# Generated by FakeRAM 2.0
VERSION 5.7 ;
BUSBITCHARS "[]" ;
PROPERTYDEFINITIONS
  MACRO width INTEGER ;
  MACRO depth INTEGER ;
  MACRO banks INTEGER ;
END PROPERTYDEFINITIONS
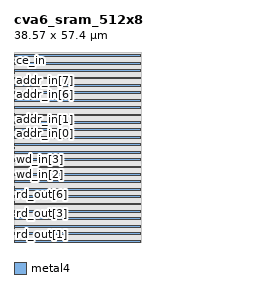
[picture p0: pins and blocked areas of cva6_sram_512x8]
MACRO cva6_sram_512x8
  PROPERTY width 8 ;
  PROPERTY depth 512 ;
  PROPERTY banks 1 ;
  FOREIGN cva6_sram_512x8 0 0 ;
  SYMMETRY X Y R90 ;
  SIZE 38.5700 BY 57.4000 ;
  CLASS BLOCK ;
  PIN rd_out[0]
    DIRECTION OUTPUT ;
    USE SIGNAL ;
    PORT
      LAYER metal4 ;
      RECT 0.00000 0.28000 0.14000 0.42000 ;
    END
  END rd_out[0]
  PIN rd_out[1]
    DIRECTION OUTPUT ;
    USE SIGNAL ;
    PORT
      LAYER metal4 ;
      RECT 0.00000 2.24000 0.14000 2.38000 ;
    END
  END rd_out[1]
  PIN rd_out[2]
    DIRECTION OUTPUT ;
    USE SIGNAL ;
    PORT
      LAYER metal4 ;
      RECT 0.00000 4.20000 0.14000 4.34000 ;
    END
  END rd_out[2]
  PIN rd_out[3]
    DIRECTION OUTPUT ;
    USE SIGNAL ;
    PORT
      LAYER metal4 ;
      RECT 0.00000 6.16000 0.14000 6.30000 ;
    END
  END rd_out[3]
  PIN rd_out[4]
    DIRECTION OUTPUT ;
    USE SIGNAL ;
    PORT
      LAYER metal4 ;
      RECT 0.00000 8.12000 0.14000 8.26000 ;
    END
  END rd_out[4]
  PIN rd_out[5]
    DIRECTION OUTPUT ;
    USE SIGNAL ;
    PORT
      LAYER metal4 ;
      RECT 0.00000 10.08000 0.14000 10.22000 ;
    END
  END rd_out[5]
  PIN rd_out[6]
    DIRECTION OUTPUT ;
    USE SIGNAL ;
    PORT
      LAYER metal4 ;
      RECT 0.00000 12.04000 0.14000 12.18000 ;
    END
  END rd_out[6]
  PIN rd_out[7]
    DIRECTION OUTPUT ;
    USE SIGNAL ;
    PORT
      LAYER metal4 ;
      RECT 0.00000 14.00000 0.14000 14.14000 ;
    END
  END rd_out[7]
  PIN wd_in[0]
    DIRECTION INPUT ;
    USE SIGNAL ;
    PORT
      LAYER metal4 ;
      RECT 0.00000 16.52000 0.14000 16.66000 ;
    END
  END wd_in[0]
  PIN wd_in[1]
    DIRECTION INPUT ;
    USE SIGNAL ;
    PORT
      LAYER metal4 ;
      RECT 0.00000 18.48000 0.14000 18.62000 ;
    END
  END wd_in[1]
  PIN wd_in[2]
    DIRECTION INPUT ;
    USE SIGNAL ;
    PORT
      LAYER metal4 ;
      RECT 0.00000 20.44000 0.14000 20.58000 ;
    END
  END wd_in[2]
  PIN wd_in[3]
    DIRECTION INPUT ;
    USE SIGNAL ;
    PORT
      LAYER metal4 ;
      RECT 0.00000 22.40000 0.14000 22.54000 ;
    END
  END wd_in[3]
  PIN wd_in[4]
    DIRECTION INPUT ;
    USE SIGNAL ;
    PORT
      LAYER metal4 ;
      RECT 0.00000 24.36000 0.14000 24.50000 ;
    END
  END wd_in[4]
  PIN wd_in[5]
    DIRECTION INPUT ;
    USE SIGNAL ;
    PORT
      LAYER metal4 ;
      RECT 0.00000 26.32000 0.14000 26.46000 ;
    END
  END wd_in[5]
  PIN wd_in[6]
    DIRECTION INPUT ;
    USE SIGNAL ;
    PORT
      LAYER metal4 ;
      RECT 0.00000 28.28000 0.14000 28.42000 ;
    END
  END wd_in[6]
  PIN wd_in[7]
    DIRECTION INPUT ;
    USE SIGNAL ;
    PORT
      LAYER metal4 ;
      RECT 0.00000 30.24000 0.14000 30.38000 ;
    END
  END wd_in[7]
  PIN addr_in[0]
    DIRECTION INPUT ;
    USE SIGNAL ;
    PORT
      LAYER metal4 ;
      RECT 0.00000 32.76000 0.14000 32.90000 ;
    END
  END addr_in[0]
  PIN addr_in[1]
    DIRECTION INPUT ;
    USE SIGNAL ;
    PORT
      LAYER metal4 ;
      RECT 0.00000 34.72000 0.14000 34.86000 ;
    END
  END addr_in[1]
  PIN addr_in[2]
    DIRECTION INPUT ;
    USE SIGNAL ;
    PORT
      LAYER metal4 ;
      RECT 0.00000 36.68000 0.14000 36.82000 ;
    END
  END addr_in[2]
  PIN addr_in[3]
    DIRECTION INPUT ;
    USE SIGNAL ;
    PORT
      LAYER metal4 ;
      RECT 0.00000 38.64000 0.14000 38.78000 ;
    END
  END addr_in[3]
  PIN addr_in[4]
    DIRECTION INPUT ;
    USE SIGNAL ;
    PORT
      LAYER metal4 ;
      RECT 0.00000 40.60000 0.14000 40.74000 ;
    END
  END addr_in[4]
  PIN addr_in[5]
    DIRECTION INPUT ;
    USE SIGNAL ;
    PORT
      LAYER metal4 ;
      RECT 0.00000 42.56000 0.14000 42.70000 ;
    END
  END addr_in[5]
  PIN addr_in[6]
    DIRECTION INPUT ;
    USE SIGNAL ;
    PORT
      LAYER metal4 ;
      RECT 0.00000 44.52000 0.14000 44.66000 ;
    END
  END addr_in[6]
  PIN addr_in[7]
    DIRECTION INPUT ;
    USE SIGNAL ;
    PORT
      LAYER metal4 ;
      RECT 0.00000 46.48000 0.14000 46.62000 ;
    END
  END addr_in[7]
  PIN addr_in[8]
    DIRECTION INPUT ;
    USE SIGNAL ;
    PORT
      LAYER metal4 ;
      RECT 0.00000 48.44000 0.14000 48.58000 ;
    END
  END addr_in[8]
  PIN we_in
    DIRECTION INPUT ;
    USE SIGNAL ;
    PORT
      LAYER metal4 ;
      RECT 0.00000 50.96000 0.14000 51.10000 ;
    END
  END we_in
  PIN clk
    DIRECTION INPUT ;
    USE SIGNAL ;
    PORT
      LAYER metal4 ;
      RECT 0.00000 52.92000 0.14000 53.06000 ;
    END
  END clk
  PIN ce_in
    DIRECTION INPUT ;
    USE SIGNAL ;
    PORT
      LAYER metal4 ;
      RECT 0.00000 54.88000 0.14000 55.02000 ;
    END
  END ce_in
  PIN VDD
    DIRECTION INOUT ;
    USE POWER ;
    PORT
      LAYER metal4 ;
      RECT 0.28000 2.24000 38.29000 2.80000 ;
      RECT 0.28000 6.72000 38.29000 7.28000 ;
      RECT 0.28000 11.20000 38.29000 11.76000 ;
      RECT 0.28000 15.68000 38.29000 16.24000 ;
      RECT 0.28000 20.16000 38.29000 20.72000 ;
      RECT 0.28000 24.64000 38.29000 25.20000 ;
      RECT 0.28000 29.12000 38.29000 29.68000 ;
      RECT 0.28000 33.60000 38.29000 34.16000 ;
      RECT 0.28000 38.08000 38.29000 38.64000 ;
      RECT 0.28000 42.56000 38.29000 43.12000 ;
      RECT 0.28000 47.04000 38.29000 47.60000 ;
      RECT 0.28000 51.52000 38.29000 52.08000 ;
      RECT 0.28000 56.00000 38.29000 56.56000 ;
    END
  END VDD
  PIN VSS
    DIRECTION INOUT ;
    USE GROUND ;
    PORT
      LAYER metal4 ;
      RECT 0.28000 0.00000 38.29000 0.56000 ;
      RECT 0.28000 4.48000 38.29000 5.04000 ;
      RECT 0.28000 8.96000 38.29000 9.52000 ;
      RECT 0.28000 13.44000 38.29000 14.00000 ;
      RECT 0.28000 17.92000 38.29000 18.48000 ;
      RECT 0.28000 22.40000 38.29000 22.96000 ;
      RECT 0.28000 26.88000 38.29000 27.44000 ;
      RECT 0.28000 31.36000 38.29000 31.92000 ;
      RECT 0.28000 35.84000 38.29000 36.40000 ;
      RECT 0.28000 40.32000 38.29000 40.88000 ;
      RECT 0.28000 44.80000 38.29000 45.36000 ;
      RECT 0.28000 49.28000 38.29000 49.84000 ;
      RECT 0.28000 53.76000 38.29000 54.32000 ;
    END
  END VSS
  OBS
    LAYER metal1 ;
    RECT 0 0 38.57000 57.40000 ;
    LAYER metal2 ;
    RECT 0 0 38.57000 57.40000 ;
    LAYER metal3 ;
    RECT 0 0 38.57000 57.40000 ;
    LAYER metal4 ;
    RECT 0 0 38.57000 57.40000 ;
  END
END cva6_sram_512x8

END LIBRARY
